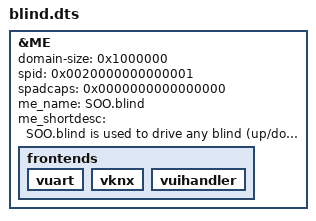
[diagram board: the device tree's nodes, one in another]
/*
 * Copyright (C) 2022 Mattia Gallacchi <mattia.gallacchi@heig-vd.ch>
 *
 * This program is free software; you can redistribute it and/or modify
 * it under the terms of the GNU General Public License version 2 as
 * published by the Free Software Foundation.
 *
 * This program is distributed in the hope that it will be useful,
 * but WITHOUT ANY WARRANTY; without even the implied warranty of
 * MERCHANTABILITY or FITNESS FOR A PARTICULAR PURPOSE.  See the
 * GNU General Public License for more details.
 *
 * You should have received a copy of the GNU General Public License
 * along with this program; if not, write to the Free Software
 * Foundation, Inc., 51 Franklin St, Fifth Floor, Boston, MA  02110-1301  USA
 *
 */

/dts-v1/;

#include "soo.dtsi"

&ME {
	/* 16 MB is enough */
	domain-size =  <0x1000000>;
	
	/* SPID on 128-bit encoding */
	spid = /bits/ 64 <0x0020000000000001>;

	/* SPAD capabilities on 64-bit encoding */
	spadcaps = /bits/ 64 <0x0000000000000000>;
		
	/* Name of this ME */
	me_name = "SOO.blind";
		
	/* Short description */
	me_shortdesc =
			
"SOO.blind is used to drive any blind (up/down position) and can manage \
various parameters from other ME like SOO.outdoor to get smarter.";

	frontends {
		
		/* Enabling the console */
		vuart {
			status = "ok";
		};
	
		vknx {
			status = "ok";
		};
        
		vuihandler {
			status = "ok";
		};
	};
	
};
	
